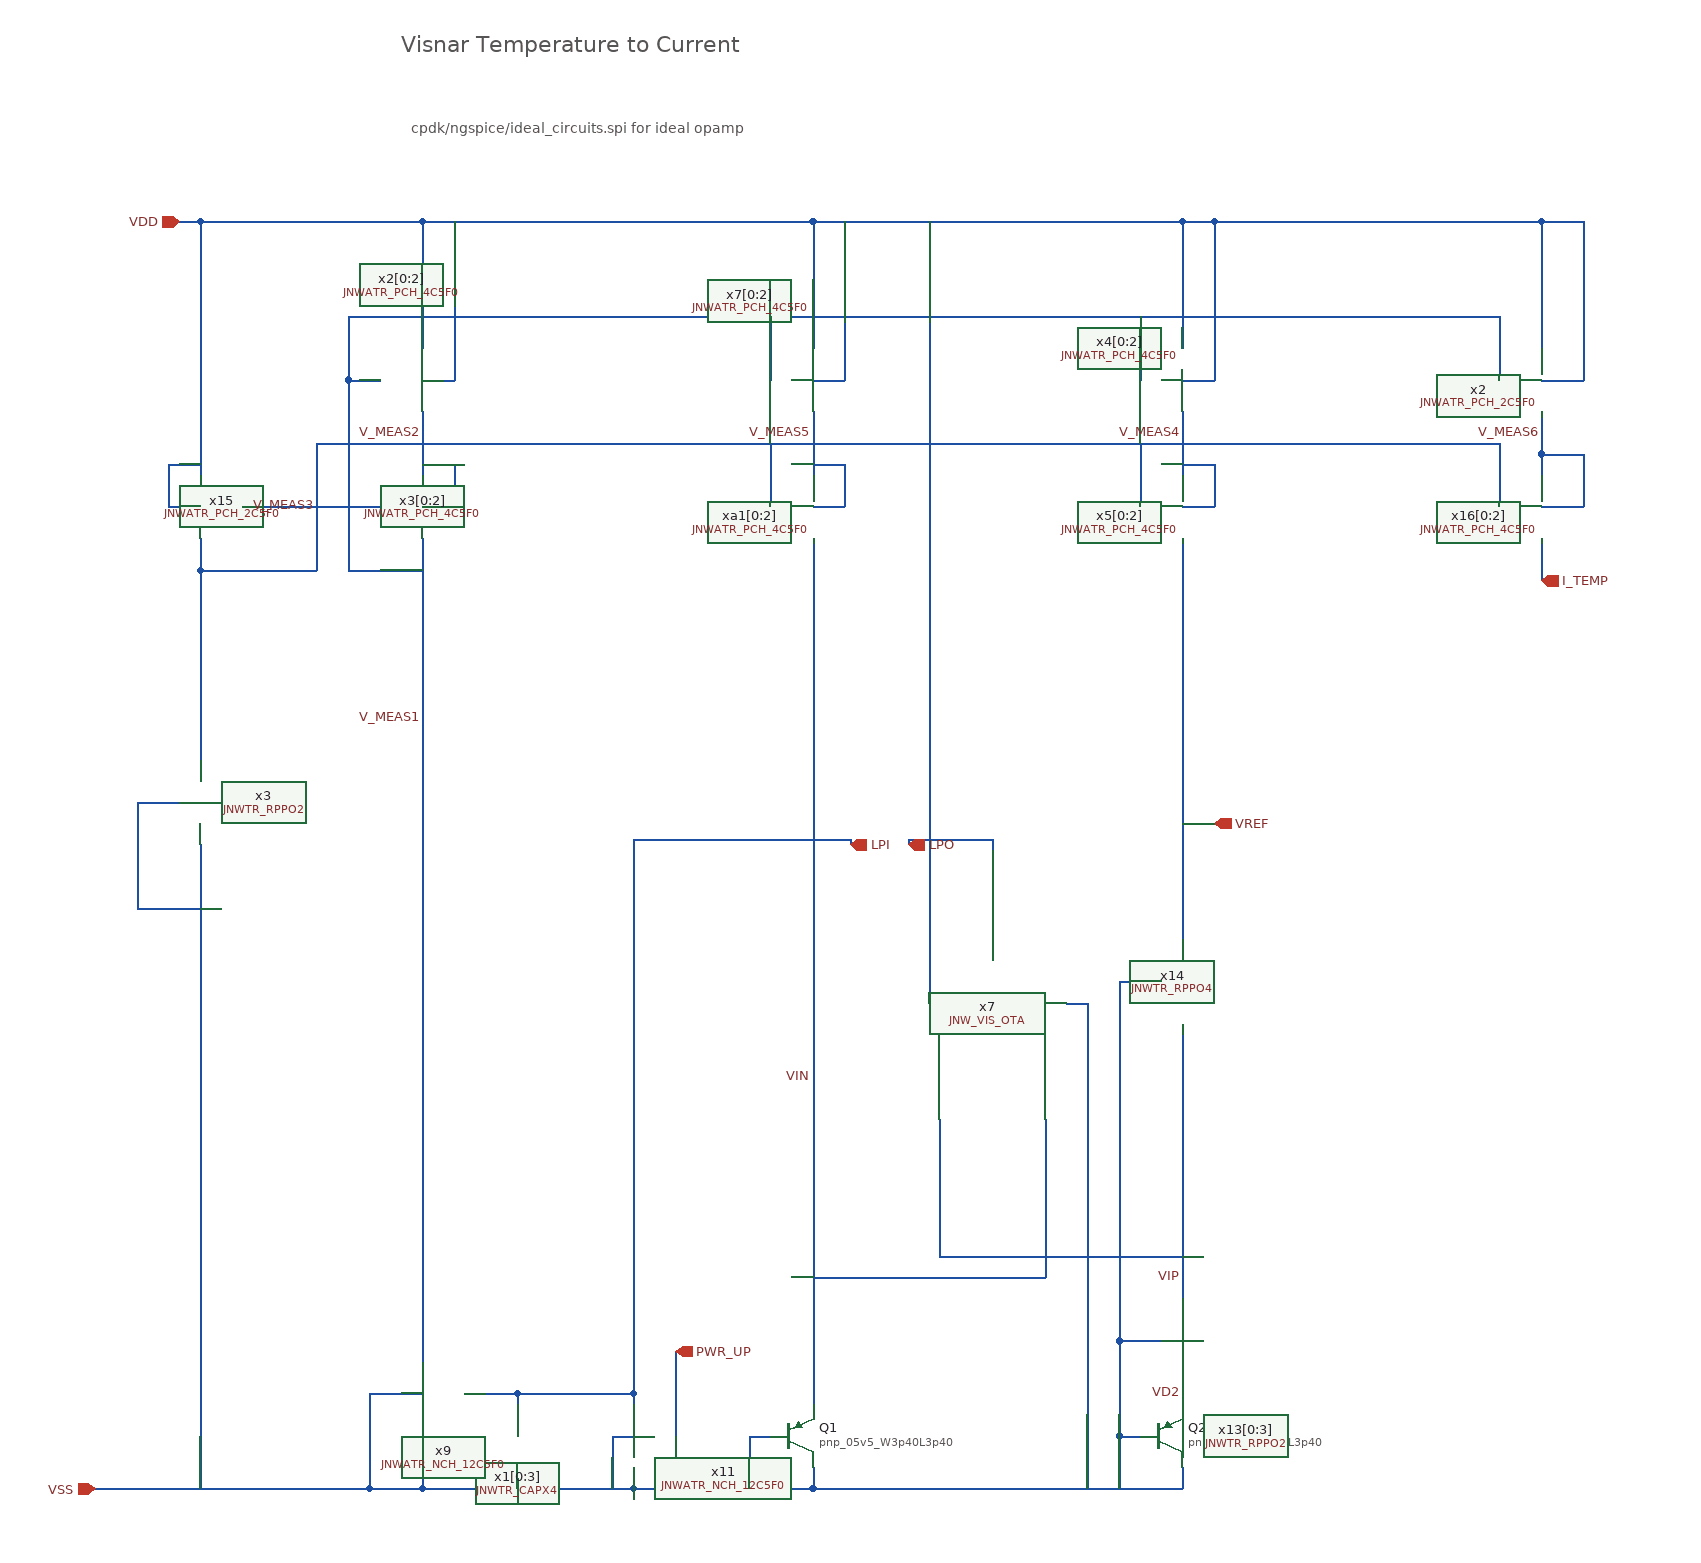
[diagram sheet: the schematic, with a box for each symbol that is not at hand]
v {xschem version=3.4.6 file_version=1.2}
G {}
K {}
V {}
S {}
E {}
T {Visnar Temperature to Current} -910 -1050 0 0 1 1 {}
T {cpdk/ngspice/ideal_circuits.spi for ideal opamp} -900 -970 0 0 0.4 0.4 {}
N -890 -280 -890 -170 {lab=V_MEAS1}
N -940 330 -890 330 {lab=VSS}
N -890 270 -890 330 {lab=VSS}
N -520 -320 -520 -150 {lab=VIN}
N -520 230 -520 250 {lab=VIN}
N -690 330 -520 330 {lab=VSS}
N -520 310 -520 330 {lab=VSS}
N -580 280 -560 280 {lab=VSS}
N -580 280 -580 330 {lab=VSS}
N -520 330 -350 330 {lab=VSS}
N -170 310 -170 330 {lab=VSS}
N -230 280 -210 280 {lab=VSS}
N -230 280 -230 330 {lab=VSS}
N -170 230 -170 250 {lab=VD2}
N -890 -170 -890 70 {lab=V_MEAS1}
N -520 -150 -520 90 {lab=VIN}
N -350 330 -170 330 {lab=VSS}
N -890 330 -690 330 {lab=VSS}
N -800 240 -800 250 {lab=LPI}
N -850 240 -800 240 {lab=LPI}
N -800 320 -800 330 {lab=VSS}
N -800 240 -690 240 {lab=LPI}
N -690 -270 -690 100 {lab=LPI}
N -690 -280 -690 -270 {lab=LPI}
N -350 -280 -350 -275 {lab=LPO}
N -690 -285 -690 -280 {lab=LPI}
N -350 -285 -350 -280 {lab=LPO}
N -410 -430 -410 -130 {lab=VDD}
N -280 -130 -260 -130 {lab=VSS}
N -260 -130 -260 190 {lab=VSS}
N -170 -320 -170 -280 {lab=VREF}
N -170 -300 -140 -300 {lab=VREF}
N -990 330 -940 330 {lab=VSS}
N -430 -285 -350 -285 {lab=LPO}
N -430 -285 -430 -280 {lab=LPO}
N -485 -285 -485 -280 {lab=LPI}
N -690 -285 -485 -285 {lab=LPI}
N -940 240 -890 240 {lab=VSS}
N -300 120 -300 130 {lab=VIN}
N -690 240 -690 250 {lab=LPI}
N -690 310 -690 330 {lab=VSS}
N -650 200 -650 280 {lab=PWR_UP}
N -710 280 -690 280 {lab=VSS}
N -710 280 -710 330 {lab=VSS}
N -1120 -870 -1100 -870 {lab=VDD}
N -890 -870 -890 -750 {lab=VDD}
N -1100 -870 -890 -870 {lab=VDD}
N -890 -870 -520 -870 {lab=VDD}
N -520 -870 -520 -750 {lab=VDD}
N -520 -870 -170 -870 {lab=VDD}
N -170 -870 -170 -750 {lab=VDD}
N -890 -690 -890 -630 {lab=V_MEAS2}
N -520 -690 -520 -630 {lab=V_MEAS5}
N -170 -690 -170 -630 {lab=V_MEAS4}
N -210 -780 -210 -720 {lab=V_MEAS1}
N -560 -780 -560 -720 {lab=V_MEAS1}
N -890 -570 -890 -480 {lab=V_MEAS1}
N -1100 -870 -1100 -630 {lab=VDD}
N -1060 -600 -930 -600 {lab=V_MEAS3}
N -1100 -540 -990 -540 {lab=V_MEAS3}
N -990 -600 -990 -540 {lab=V_MEAS3}
N -960 -540 -890 -540 {lab=V_MEAS1}
N -960 -720 -960 -540 {lab=V_MEAS1}
N -960 -720 -930 -720 {lab=V_MEAS1}
N -990 -660 -990 -600 {lab=V_MEAS3}
N -560 -660 -560 -600 {lab=V_MEAS3}
N -990 -660 -40 -660 {lab=V_MEAS3}
N -210 -660 -210 -600 {lab=V_MEAS3}
N -960 -780 -960 -720 {lab=V_MEAS1}
N -960 -780 -40 -780 {lab=V_MEAS1}
N -890 -720 -860 -720 {lab=VDD}
N -860 -870 -860 -720 {lab=VDD}
N -520 -720 -490 -720 {lab=VDD}
N -490 -870 -490 -720 {lab=VDD}
N -170 -720 -140 -720 {lab=VDD}
N -140 -870 -140 -720 {lab=VDD}
N -170 -600 -140 -600 {lab=V_MEAS4}
N -140 -640 -140 -600 {lab=V_MEAS4}
N -520 -600 -490 -600 {lab=V_MEAS5}
N -490 -640 -490 -600 {lab=V_MEAS5}
N -1130 -600 -1100 -600 {lab=VDD}
N -1130 -640 -1130 -600 {lab=VDD}
N -1130 -640 -1100 -640 {lab=VDD}
N -1200 330 -990 330 {lab=VSS}
N -1100 -540 -1100 -460 {lab=V_MEAS3}
N -1100 -570 -1100 -540 {lab=V_MEAS3}
N -520 -570 -520 -320 {lab=VIN}
N -410 -870 -410 -430 {lab=VDD}
N -170 -570 -170 -320 {lab=VREF}
N -1100 -100 -1100 190 {lab=VSS}
N -520 90 -520 230 {lab=VIN}
N -260 190 -260 330 {lab=VSS}
N -170 -280 -170 -260 {lab=VREF}
N -1100 190 -1100 330 {lab=VSS}
N -890 70 -890 210 {lab=V_MEAS1}
N -690 100 -690 240 {lab=LPI}
N -300 -20 -300 120 {lab=VIN}
N -170 -110 -170 -90 {lab=VIP}
N -170 -200 -170 -190 {lab=VREF}
N -230 190 -190 190 {lab=VSS}
N -230 190 -230 280 {lab=VSS}
N -230 -150 -230 190 {lab=VSS}
N -230 -150 -190 -150 {lab=VSS}
N -1100 -280 -1100 -260 {lab=VSS}
N -1100 -370 -1100 -360 {lab=V_MEAS3}
N -1160 -320 -1120 -320 {lab=VSS}
N -1100 -140 -1100 -100 {lab=VSS}
N -1100 -400 -1100 -370 {lab=V_MEAS3}
N -890 -480 -890 -340 {lab=V_MEAS1}
N -890 -340 -890 -280 {lab=V_MEAS1}
N -1100 -460 -1100 -400 {lab=V_MEAS3}
N -170 -260 -170 -200 {lab=VREF}
N -170 -870 -140 -870 {lab=VDD}
N -140 -870 0 -870 {lab=VDD}
N 0 -870 140 -870 {lab=VDD}
N -940 240 -940 330 {lab=VSS}
N -520 130 -300 130 {lab=VIN}
N 170 -870 170 -750 {lab=VDD}
N 170 -720 210 -720 {lab=VDD}
N 210 -870 210 -720 {lab=VDD}
N 170 -870 210 -870 {lab=VDD}
N 130 -780 130 -720 {lab=V_MEAS1}
N 170 -690 170 -650 {lab=V_MEAS6}
N 140 -870 170 -870 {lab=VDD}
N -40 -780 130 -780 {lab=V_MEAS1}
N -170 -10 -170 10 {lab=VIP}
N -400 -20 -400 20 {lab=VIP}
N -170 140 -170 150 {lab=VIP}
N -170 10 -170 20 {lab=VIP}
N -170 100 -170 140 {lab=VIP}
N -400 20 -400 110 {lab=VIP}
N -400 110 -170 110 {lab=VIP}
N 170 -650 170 -630 {lab=V_MEAS6}
N 130 -660 130 -600 {lab=V_MEAS3}
N -40 -660 130 -660 {lab=V_MEAS3}
N 170 -570 170 -530 {lab=I_TEMP}
N 170 -600 210 -600 {lab=V_MEAS6}
N 210 -650 210 -600 {lab=V_MEAS6}
N -170 -90 -170 -10 {lab=VIP}
N -1100 -260 -1100 -140 {lab=VSS}
N -1160 -320 -1160 -220 {lab=VSS}
N -1160 -220 -1100 -220 {lab=VSS}
N -890 -600 -860 -600 {lab=V_MEAS2}
N -170 20 -170 100 {lab=VIP}
N 170 -650 210 -650 {lab=V_MEAS6}
N -170 -640 -140 -640 {lab=V_MEAS4}
N -520 -640 -490 -640 {lab=V_MEAS5}
N -860 -640 -860 -600 {lab=V_MEAS2}
N -890 -640 -860 -640 {lab=V_MEAS2}
C {devices/ipin.sym} -1200 330 0 0 {name=p2 lab=VSS
}
C {sky130_fd_pr/pnp_05v5.sym} -540 280 0 0 {name=Q1
model=pnp_05v5_W3p40L3p40
m=1
spiceprefix=X
}
C {sky130_fd_pr/pnp_05v5.sym} -190 280 0 0 {name=Q2
model=pnp_05v5_W3p40L3p40
m=8
spiceprefix=X
}
C {JNW_GR02_SKY130A/JNW_VIS_OTA.sym} -210 -80 3 0 {name=x7}
C {devices/opin.sym} -140 -300 0 0 {name=p3 lab=VREF}
C {JNW_ATR_SKY130A/JNWATR_NCH_12C5F0.sym} -650 280 0 1 {name=x11}
C {devices/ipin.sym} -650 200 0 1 {name=p5 lab=PWR_UP
}
C {JNW_TR_SKY130A/JNWTR_CAPX4.sym} -800 310 0 0 {name=x1[0:3]}
C {devices/lab_wire.sym} -170 130 0 0 {name=p6 sig_type=std_logic lab=VIP}
C {devices/lab_wire.sym} -520 -60 0 0 {name=p7 sig_type=std_logic lab=VIN}
C {JNW_ATR_SKY130A/JNWATR_NCH_12C5F0.sym} -850 240 0 1 {name=x9}
C {devices/opin.sym} -485 -280 1 0 {name=p8 lab=LPI}
C {devices/opin.sym} -430 -280 1 0 {name=p9 lab=LPO}
C {devices/lab_wire.sym} -170 240 0 0 {name=p10 sig_type=std_logic lab=VD2
}
C {JNW_ATR_SKY130A/JNWATR_PCH_4C5F0.sym} -930 -720 0 0 {name=x2[0:2] }
C {JNW_ATR_SKY130A/JNWATR_PCH_4C5F0.sym} -930 -600 0 0 {name=x3[0:2] }
C {JNW_ATR_SKY130A/JNWATR_PCH_4C5F0.sym} -210 -720 0 0 {name=x4[0:2] }
C {JNW_ATR_SKY130A/JNWATR_PCH_4C5F0.sym} -210 -600 0 0 {name=x5[0:2] }
C {JNW_ATR_SKY130A/JNWATR_PCH_2C5F0.sym} -1060 -600 0 1 {name=x15}
C {devices/ipin.sym} -1120 -870 0 0 {name=p11 lab=VDD}
C {JNW_ATR_SKY130A/JNWATR_PCH_4C5F0.sym} -560 -720 0 0 {name=x7[0:2] }
C {JNW_ATR_SKY130A/JNWATR_PCH_4C5F0.sym} -560 -600 0 0 {name=xa1[0:2] }
C {devices/lab_wire.sym} -890 -400 0 0 {name=p1 sig_type=std_logic lab=V_MEAS1}
C {devices/lab_wire.sym} -890 -670 0 0 {name=p12 sig_type=std_logic lab=V_MEAS2}
C {JNW_TR_SKY130A/JNWTR_RPPO4.sym} -170 -190 1 0 {name=x14}
C {JNW_TR_SKY130A/JNWTR_RPPO2.sym} -170 150 1 0 {name=x13[0:3]}
C {JNW_TR_SKY130A/JNWTR_RPPO2.sym} -1100 -360 1 0 {name=x3}
C {devices/lab_wire.sym} -990 -600 0 0 {name=p13 sig_type=std_logic lab=V_MEAS3}
C {devices/opin.sym} 170 -530 1 0 {name=p4 lab=I_TEMP}
C {JNW_ATR_SKY130A/JNWATR_PCH_2C5F0.sym} 130 -720 0 0 {name=x2}
C {devices/lab_wire.sym} -170 -670 0 0 {name=p14 sig_type=std_logic lab=V_MEAS4}
C {JNW_ATR_SKY130A/JNWATR_PCH_4C5F0.sym} 130 -600 0 0 {name=x16[0:2] }
C {devices/lab_wire.sym} -520 -670 0 0 {name=p15 sig_type=std_logic lab=V_MEAS5}
C {devices/lab_wire.sym} 170 -670 0 0 {name=p16 sig_type=std_logic lab=V_MEAS6}
